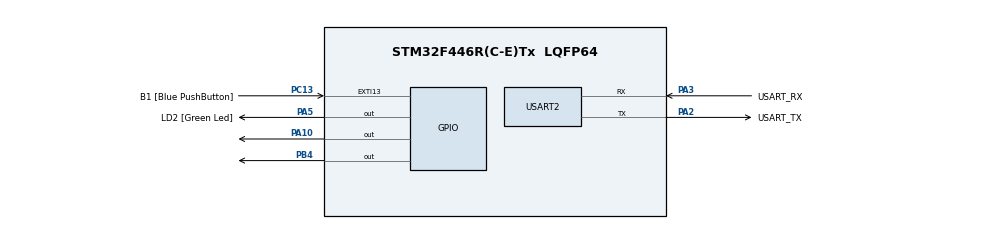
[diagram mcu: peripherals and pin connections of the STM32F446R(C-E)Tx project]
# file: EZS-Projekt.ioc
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Mcu.Family=STM32F4
Mcu.Name=STM32F446R(C-E)Tx
Mcu.Package=LQFP64
NVIC.PriorityGroup=NVIC_PRIORITYGROUP_2
NVIC.TIM2_IRQn=true\:0\:0\:true\:false\:true\:true\:true\:true
NVIC.TIM3_IRQn=true\:1\:0\:true\:false\:true\:true\:true\:true
PA10.Signal=GPIO_Output
PA13.GPIO_Label=TMS
PA13.Mode=Serial_Wire
PA13.Signal=SYS_JTMS-SWDIO
PA14.GPIO_Label=TCK
PA14.Mode=Serial_Wire
PA14.Signal=SYS_JTCK-SWCLK
PA2.GPIO_Label=USART_TX
PA2.Mode=Asynchronous
PA2.Signal=USART2_TX
PA3.GPIO_Label=USART_RX
PA3.Mode=Asynchronous
PA3.Signal=USART2_RX
PA5.GPIO_Label=LD2 [Green Led]
PA5.Signal=GPIO_Output
PB3.GPIO_Label=SWO
PB3.Signal=SYS_JTDO-SWO
PB4.Signal=GPIO_Output
PC13.GPIO_Label=B1 [Blue PushButton]
PC13.GPIO_ModeDefaultEXTI=GPIO_MODE_IT_FALLING
PC13.Signal=GPXTI13
PC14-OSC32_IN.Mode=LSE-External-Oscillator
PC14-OSC32_IN.Signal=RCC_OSC32_IN
PC15-OSC32_OUT.Mode=LSE-External-Oscillator
PC15-OSC32_OUT.Signal=RCC_OSC32_OUT
PH0-OSC_IN.Mode=HSE-External-Oscillator
PH0-OSC_IN.Signal=RCC_OSC_IN
PH1-OSC_OUT.Mode=HSE-External-Oscillator
PH1-OSC_OUT.Signal=RCC_OSC_OUT
ProjectManager.HeapSize=0x200
ProjectManager.StackSize=0x400
ProjectManager.TargetToolchain=STM32CubeIDE
RCC.48MHZClocksFreq_Value=84000000
RCC.AHBFreq_Value=80000000
RCC.APB1CLKDivider=RCC_HCLK_DIV2
RCC.APB1Freq_Value=40000000
RCC.APB1TimFreq_Value=80000000
RCC.APB2CLKDivider=RCC_HCLK_DIV8
RCC.APB2Freq_Value=10000000
RCC.APB2TimFreq_Value=20000000
RCC.CortexFreq_Value=80000000
RCC.FLatency-AdvancedSettings=FLASH_LATENCY_2
RCC.HCLKFreq_Value=80000000
RCC.HSE_VALUE=8000000
RCC.HSI_VALUE=16000000
RCC.PLLM=8
RCC.PLLN=80
RCC.SYSCLKFreq_VALUE=80000000
RCC.SYSCLKSource=RCC_SYSCLKSOURCE_PLLCLK
RCC.USBFreq_Value=80000000
RCC.VCOOutputFreq_Value=160000000
TIM2.AutoReloadPreload=TIM_AUTORELOAD_PRELOAD_ENABLE
TIM2.Prescaler=0
TIM3.AutoReloadPreload=TIM_AUTORELOAD_PRELOAD_ENABLE
TIM3.Prescaler=1
USART2.VirtualMode=VM_ASYNC
VP_TIM2_VS_ClockSourceINT.Mode=Internal
VP_TIM3_VS_ClockSourceINT.Mode=Internal
VP_TIM5_VS_ClockSourceINT.Mode=Internal
board=NUCLEO-F446RE

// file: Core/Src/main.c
/* USER CODE BEGIN Header */
/**
  ******************************************************************************
  * @file           : main.c
  * @brief          : Main program body
  ******************************************************************************
  * @attention
  *
  * Copyright (c) 2022 STMicroelectronics.
  * All rights reserved.
  *
  * This software is licensed under terms that can be found in the LICENSE file
  * in the root directory of this software component.
  * If no LICENSE file comes with this software, it is provided AS-IS.
  *
  ******************************************************************************
  */
/* USER CODE END Header */
#include <motion_controller.h>
#include "main.h"
#include <stdio.h>

#ifdef __GNUC__
#define PUTCHAR_PROTOTYPE int __io_putchar(int ch)
#define GETCHAR_PROTOTYPE int __io_getchar(void)
#else
#define PUTCHAR_PROTOTYPE int fputc(int ch, FILE *f)
#define GETCHAR_PROTOTYPE int fgetc(FILE *f)
#endif

UART_HandleTypeDef huart2;

UART_HandleTypeDef return_uart() {
	return huart2;
}

GETCHAR_PROTOTYPE
{
  uint8_t ch = 0;

  /* Clear the Overrun flag just before receiving the first character */
  __HAL_UART_CLEAR_OREFLAG(&huart2);

  /* Wait for reception of a character on the USART RX line and echo this
   * character on console */
  HAL_UART_Receive(&huart2, (uint8_t *)&ch, 1, HAL_MAX_DELAY);
  HAL_UART_Transmit(&huart2, (uint8_t *)&ch, 1, HAL_MAX_DELAY);
  return ch;
}

void SystemClock_Config(void);
static void MX_GPIO_Init(void);
static void MX_USART2_UART_Init(void);

#define BUTTON GPIO_PIN_13
#define LED GPIO_PIN_5
#define release 0
#define debug 1

int _write(int32_t file, uint8_t *ptr, int32_t len)
{
	HAL_UART_Transmit(&huart2, ptr, len, 2000);
	return len;
}

void resetSTDINBuf(void) {
	  setvbuf(stdin, NULL, _IONBF, 0);
}

int main(void)
{

  HAL_Init();

  /* Configure the system clock */
  SystemClock_Config();

  /* Initialize all configured peripherals */
  MX_GPIO_Init();
  HAL_GPIO_WritePin(GPIOA, LED, 0);

  MX_USART2_UART_Init();
  MX_TIM2_Init();
  MX_TIM3_Init();
  MX_TIM5_Init();
  set_motor_direction(CLOCKWISE);
  TIM_StartInterruptTimer();
  resetSTDINBuf();
  TIM_StartIntegralInterruptTimer();
  TIM_StartTrackInterruptTimer();
  uint16_t timer_val;

  char string[256];

  int angle;
  int steps;
  int dir;
  int command;
  int upm;

  while (1)
  {

#if debug
	  debug_mode(1200);
#endif

#if release
	  printf("Enter command:\n\r");
	  printf("0 = step mode\n\r1 = angle mode\n\r2 = velocity mode:\n\r3 = change direction\n\r");
	  scanf("%d", &command);

	  switch(command) {
		  case 0:
		  {
			  printf("Enter steps:\n\r");
			  scanf("%d", &steps);
			  make_n_steps(steps);
			  break;
		  }
		  case 1:
		  {
			  printf("Enter angle:\n\r");
			  scanf("%d", &angle);
			  if(angle > 0 && angle <= 10000)
				  set_motor_angle(angle);
			  break;
		  }
		  case 2:
		  {
			  printf("Enter u/min:\n\r");
			  scanf("%d", &upm);
			  velocity_mode(upm);
			  break;
		  }
		  case 3:
		  {
			  printf("Enter direction.\n\r0 = Counter clockwise\n\r1 = clockwise:\n\r");
			  scanf("%d", &dir);
			  set_motor_direction(dir);
			  break;
		  }
	  }

	  resetSTDINBuf();
#endif

  }
}

void SystemClock_Config(void)
{
  RCC_OscInitTypeDef RCC_OscInitStruct = {0};
  RCC_ClkInitTypeDef RCC_ClkInitStruct = {0};

  /** Configure the main internal regulator output voltage
  */
  __HAL_RCC_PWR_CLK_ENABLE();
  __HAL_PWR_VOLTAGESCALING_CONFIG(PWR_REGULATOR_VOLTAGE_SCALE3);

  /** Initializes the RCC Oscillators according to the specified parameters
  * in the RCC_OscInitTypeDef structure.
  */
  RCC_OscInitStruct.OscillatorType = RCC_OSCILLATORTYPE_HSI;
  RCC_OscInitStruct.HSIState = RCC_HSI_ON;
  RCC_OscInitStruct.HSICalibrationValue = RCC_HSICALIBRATION_DEFAULT;
  RCC_OscInitStruct.PLL.PLLState = RCC_PLL_ON;
  RCC_OscInitStruct.PLL.PLLSource = RCC_PLLSOURCE_HSI;
  RCC_OscInitStruct.PLL.PLLM = 8;
  RCC_OscInitStruct.PLL.PLLN = 80;
  RCC_OscInitStruct.PLL.PLLP = RCC_PLLP_DIV2;
  RCC_OscInitStruct.PLL.PLLQ = 2;
  RCC_OscInitStruct.PLL.PLLR = 2;
  if (HAL_RCC_OscConfig(&RCC_OscInitStruct) != HAL_OK)
  {
    Error_Handler();
  }

  /** Initializes the CPU, AHB and APB buses clocks
  */
  RCC_ClkInitStruct.ClockType = RCC_CLOCKTYPE_HCLK|RCC_CLOCKTYPE_SYSCLK
                              |RCC_CLOCKTYPE_PCLK1|RCC_CLOCKTYPE_PCLK2;
  RCC_ClkInitStruct.SYSCLKSource = RCC_SYSCLKSOURCE_PLLCLK;
  RCC_ClkInitStruct.AHBCLKDivider = RCC_SYSCLK_DIV1;
  RCC_ClkInitStruct.APB1CLKDivider = RCC_HCLK_DIV2;
  RCC_ClkInitStruct.APB2CLKDivider = RCC_HCLK_DIV2;

  if (HAL_RCC_ClockConfig(&RCC_ClkInitStruct, FLASH_LATENCY_2) != HAL_OK)
  {
    Error_Handler();
  }
}

static void MX_USART2_UART_Init(void)
{

  huart2.Instance = USART2;
  huart2.Init.BaudRate = 115200;
  huart2.Init.WordLength = UART_WORDLENGTH_8B;
  huart2.Init.StopBits = UART_STOPBITS_1;
  huart2.Init.Parity = UART_PARITY_NONE;
  huart2.Init.Mode = UART_MODE_TX_RX;
  huart2.Init.HwFlowCtl = UART_HWCONTROL_NONE;
  huart2.Init.OverSampling = UART_OVERSAMPLING_16;
  if (HAL_UART_Init(&huart2) != HAL_OK)
  {
    Error_Handler();
  }

}

static void MX_GPIO_Init(void)
{
  GPIO_InitTypeDef GPIO_InitStruct = {0};

  /* GPIO Ports Clock Enable */
  __HAL_RCC_GPIOC_CLK_ENABLE();
  __HAL_RCC_GPIOH_CLK_ENABLE();
  __HAL_RCC_GPIOA_CLK_ENABLE();
  __HAL_RCC_GPIOB_CLK_ENABLE();

  /*Configure GPIO pin Output Level */
  HAL_GPIO_WritePin(GPIOA, LD2_Pin|GPIO_PIN_10, GPIO_PIN_RESET);

  /*Configure GPIO pin Output Level */
  HAL_GPIO_WritePin(GPIOB, GPIO_PIN_4, GPIO_PIN_RESET);

  /*Configure GPIO pin : B1_Pin */
  GPIO_InitStruct.Pin = B1_Pin;
  GPIO_InitStruct.Mode = GPIO_MODE_IT_FALLING;
  GPIO_InitStruct.Pull = GPIO_NOPULL;
  HAL_GPIO_Init(B1_GPIO_Port, &GPIO_InitStruct);

  /*Configure GPIO pins : LD2_Pin PA10 */
  GPIO_InitStruct.Pin = LD2_Pin|GPIO_PIN_10;
  GPIO_InitStruct.Mode = GPIO_MODE_OUTPUT_PP;
  GPIO_InitStruct.Pull = GPIO_NOPULL;
  GPIO_InitStruct.Speed = GPIO_SPEED_FREQ_LOW;
  HAL_GPIO_Init(GPIOA, &GPIO_InitStruct);

  /*Configure GPIO pin : PB4 */
  GPIO_InitStruct.Pin = GPIO_PIN_4;
  GPIO_InitStruct.Mode = GPIO_MODE_OUTPUT_PP;
  GPIO_InitStruct.Pull = GPIO_NOPULL;
  GPIO_InitStruct.Speed = GPIO_SPEED_FREQ_LOW;
  HAL_GPIO_Init(GPIOB, &GPIO_InitStruct);

}

void Error_Handler(void)
{
  __disable_irq();
  while (1)
  {
  }
}
